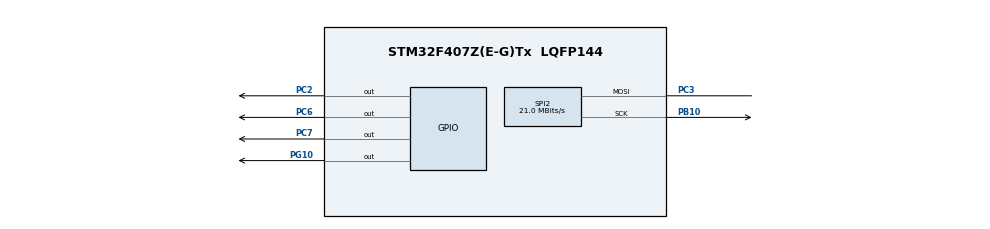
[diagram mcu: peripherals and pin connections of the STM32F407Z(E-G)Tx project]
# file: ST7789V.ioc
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Mcu.Family=STM32F4
Mcu.Name=STM32F407Z(E-G)Tx
Mcu.Package=LQFP144
NVIC.PriorityGroup=NVIC_PRIORITYGROUP_4
PB10.Mode=Simplex_Bidirectional_Master
PB10.Signal=SPI2_SCK
PC2.GPIO_Speed=GPIO_SPEED_FREQ_VERY_HIGH
PC2.Signal=GPIO_Output
PC3.Mode=Simplex_Bidirectional_Master
PC3.Signal=SPI2_MOSI
PC6.GPIO_Speed=GPIO_SPEED_FREQ_VERY_HIGH
PC6.PinState=GPIO_PIN_SET
PC6.Signal=GPIO_Output
PC7.GPIO_Speed=GPIO_SPEED_FREQ_VERY_HIGH
PC7.Signal=GPIO_Output
PG10.GPIO_Speed=GPIO_SPEED_FREQ_VERY_HIGH
PG10.PinState=GPIO_PIN_SET
PG10.Signal=GPIO_Output
PH0-OSC_IN.Mode=HSE-External-Oscillator
PH0-OSC_IN.Signal=RCC_OSC_IN
PH1-OSC_OUT.Mode=HSE-External-Oscillator
PH1-OSC_OUT.Signal=RCC_OSC_OUT
ProjectManager.HeapSize=0x800
ProjectManager.StackSize=0x800
ProjectManager.TargetToolchain=TrueSTUDIO
RCC.48MHZClocksFreq_Value=42000000
RCC.AHBFreq_Value=84000000
RCC.APB1CLKDivider=RCC_HCLK_DIV2
RCC.APB1Freq_Value=42000000
RCC.APB1TimFreq_Value=84000000
RCC.APB2CLKDivider=RCC_HCLK_DIV2
RCC.APB2Freq_Value=42000000
RCC.APB2TimFreq_Value=84000000
RCC.CortexFreq_Value=84000000
RCC.HCLKFreq_Value=84000000
RCC.HSE_VALUE=12000000
RCC.HSI_VALUE=16000000
RCC.LSE_VALUE=32768
RCC.PLLM=6
RCC.PLLN=84
RCC.PLLSourceVirtual=RCC_PLLSOURCE_HSE
RCC.SYSCLKFreq_VALUE=84000000
RCC.SYSCLKSource=RCC_SYSCLKSOURCE_PLLCLK
RCC.VCOOutputFreq_Value=168000000
SPI2.BaudRatePrescaler=SPI_BAUDRATEPRESCALER_2
SPI2.CLKPolarity=SPI_POLARITY_LOW
SPI2.CalculateBaudRate=21.0 MBits/s
SPI2.Direction=SPI_DIRECTION_1LINE
SPI2.Mode=SPI_MODE_MASTER
SPI2.VirtualType=VM_MASTER
board=custom

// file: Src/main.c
/* USER CODE BEGIN Header */
/**
  ******************************************************************************
  * @file           : main.c
  * @brief          : Main program body
  ******************************************************************************
  ** This notice applies to any and all portions of this file
  * that are not between comment pairs USER CODE BEGIN and
  * USER CODE END. Other portions of this file, whether
  * inserted by the user or by software development tools
  * are owned by their respective copyright owners.
  *
  * COPYRIGHT(c) 2019 STMicroelectronics
  *
  * Redistribution and use in source and binary forms, with or without modification,
  * are permitted provided that the following conditions are met:
  *   1. Redistributions of source code must retain the above copyright notice,
  *      this list of conditions and the following disclaimer.
  *   2. Redistributions in binary form must reproduce the above copyright notice,
  *      this list of conditions and the following disclaimer in the documentation
  *      and/or other materials provided with the distribution.
  *   3. Neither the name of STMicroelectronics nor the names of its contributors
  *      may be used to endorse or promote products derived from this software
  *      without specific prior written permission.
  *
  * THIS SOFTWARE IS PROVIDED BY THE COPYRIGHT HOLDERS AND CONTRIBUTORS "AS IS"
  * AND ANY EXPRESS OR IMPLIED WARRANTIES, INCLUDING, BUT NOT LIMITED TO, THE
  * IMPLIED WARRANTIES OF MERCHANTABILITY AND FITNESS FOR A PARTICULAR PURPOSE ARE
  * DISCLAIMED. IN NO EVENT SHALL THE COPYRIGHT HOLDER OR CONTRIBUTORS BE LIABLE
  * FOR ANY DIRECT, INDIRECT, INCIDENTAL, SPECIAL, EXEMPLARY, OR CONSEQUENTIAL
  * DAMAGES (INCLUDING, BUT NOT LIMITED TO, PROCUREMENT OF SUBSTITUTE GOODS OR
  * SERVICES; LOSS OF USE, DATA, OR PROFITS; OR BUSINESS INTERRUPTION) HOWEVER
  * CAUSED AND ON ANY THEORY OF LIABILITY, WHETHER IN CONTRACT, STRICT LIABILITY,
  * OR TORT (INCLUDING NEGLIGENCE OR OTHERWISE) ARISING IN ANY WAY OUT OF THE USE
  * OF THIS SOFTWARE, EVEN IF ADVISED OF THE POSSIBILITY OF SUCH DAMAGE.
  *
  ******************************************************************************
  */
/* USER CODE END Header */

#include "main.h"

/* USER CODE BEGIN Includes */
#include "st7789v.h"
/* USER CODE END Includes */

SPI_HandleTypeDef hspi2;

void SystemClock_Config(void);
static void MX_GPIO_Init(void);
static void MX_SPI2_Init(void);

int main(void)
{

  /* MCU Configuration--------------------------------------------------------*/

  /* Reset of all peripherals, Initializes the Flash interface and the Systick. */
  HAL_Init();

  /* Configure the system clock */
  SystemClock_Config();

  /* Initialize all configured peripherals */
  MX_GPIO_Init();
  MX_SPI2_Init();
  /* USER CODE BEGIN 2 */
  display_init();
  /* USER CODE END 2 */

  /* Infinite loop */
  while (1)
  {

    /* USER CODE BEGIN 3 */
	HAL_GPIO_WritePin(GPIOC, GPIO_PIN_2, 1);
	white_line();
	HAL_GPIO_WritePin(GPIOC, GPIO_PIN_2, 0);
	//white();
	//HAL_Delay(1000);
	black_line();
	//black();
	//HAL_Delay(1000);
  }
  /* USER CODE END 3 */
}

void SystemClock_Config(void)
{
  RCC_OscInitTypeDef RCC_OscInitStruct = {0};
  RCC_ClkInitTypeDef RCC_ClkInitStruct = {0};

  /**Configure the main internal regulator output voltage
  */
  __HAL_RCC_PWR_CLK_ENABLE();
  __HAL_PWR_VOLTAGESCALING_CONFIG(PWR_REGULATOR_VOLTAGE_SCALE1);
  /**Initializes the CPU, AHB and APB busses clocks
  */
  RCC_OscInitStruct.OscillatorType = RCC_OSCILLATORTYPE_HSE;
  RCC_OscInitStruct.HSEState = RCC_HSE_ON;
  RCC_OscInitStruct.PLL.PLLState = RCC_PLL_ON;
  RCC_OscInitStruct.PLL.PLLSource = RCC_PLLSOURCE_HSE;
  RCC_OscInitStruct.PLL.PLLM = 6;
  RCC_OscInitStruct.PLL.PLLN = 84;
  RCC_OscInitStruct.PLL.PLLP = RCC_PLLP_DIV2;
  RCC_OscInitStruct.PLL.PLLQ = 4;
  if (HAL_RCC_OscConfig(&RCC_OscInitStruct) != HAL_OK)
  {
    Error_Handler();
  }
  /**Initializes the CPU, AHB and APB busses clocks
  */
  RCC_ClkInitStruct.ClockType = RCC_CLOCKTYPE_HCLK|RCC_CLOCKTYPE_SYSCLK
                              |RCC_CLOCKTYPE_PCLK1|RCC_CLOCKTYPE_PCLK2;
  RCC_ClkInitStruct.SYSCLKSource = RCC_SYSCLKSOURCE_PLLCLK;
  RCC_ClkInitStruct.AHBCLKDivider = RCC_SYSCLK_DIV1;
  RCC_ClkInitStruct.APB1CLKDivider = RCC_HCLK_DIV1;
  RCC_ClkInitStruct.APB2CLKDivider = RCC_HCLK_DIV2;

  if (HAL_RCC_ClockConfig(&RCC_ClkInitStruct, FLASH_LATENCY_2) != HAL_OK)
  {
    Error_Handler();
  }
}

static void MX_SPI2_Init(void)
{

  /* SPI2 parameter configuration*/
  hspi2.Instance = SPI2;
  hspi2.Init.Mode = SPI_MODE_MASTER;
  hspi2.Init.Direction = SPI_DIRECTION_1LINE;
  hspi2.Init.DataSize = SPI_DATASIZE_8BIT;
  hspi2.Init.CLKPolarity = SPI_POLARITY_LOW;
  hspi2.Init.CLKPhase = SPI_PHASE_1EDGE;
  hspi2.Init.NSS = SPI_NSS_SOFT;
  hspi2.Init.BaudRatePrescaler = SPI_BAUDRATEPRESCALER_2;
  hspi2.Init.FirstBit = SPI_FIRSTBIT_MSB;
  hspi2.Init.TIMode = SPI_TIMODE_DISABLE;
  hspi2.Init.CRCCalculation = SPI_CRCCALCULATION_DISABLE;
  hspi2.Init.CRCPolynomial = 10;
  if (HAL_SPI_Init(&hspi2) != HAL_OK)
  {
    Error_Handler();
  }

}

static void MX_GPIO_Init(void)
{
  GPIO_InitTypeDef GPIO_InitStruct = {0};

  /* GPIO Ports Clock Enable */
  __HAL_RCC_GPIOH_CLK_ENABLE();
  __HAL_RCC_GPIOC_CLK_ENABLE();
  __HAL_RCC_GPIOB_CLK_ENABLE();
  __HAL_RCC_GPIOG_CLK_ENABLE();

  /*Configure GPIO pin Output Level */
  HAL_GPIO_WritePin(GPIOC, GPIO_PIN_2|GPIO_PIN_7, GPIO_PIN_RESET);

  /*Configure GPIO pin Output Level */
  HAL_GPIO_WritePin(GPIOC, GPIO_PIN_6, GPIO_PIN_SET);

  /*Configure GPIO pin Output Level */
  HAL_GPIO_WritePin(GPIOG, GPIO_PIN_10, GPIO_PIN_SET);

  /*Configure GPIO pins : PC2 PC6 PC7 */
  GPIO_InitStruct.Pin = GPIO_PIN_2|GPIO_PIN_6|GPIO_PIN_7;
  GPIO_InitStruct.Mode = GPIO_MODE_OUTPUT_PP;
  GPIO_InitStruct.Pull = GPIO_NOPULL;
  GPIO_InitStruct.Speed = GPIO_SPEED_FREQ_VERY_HIGH;
  HAL_GPIO_Init(GPIOC, &GPIO_InitStruct);

  /*Configure GPIO pin : PG10 */
  GPIO_InitStruct.Pin = GPIO_PIN_10;
  GPIO_InitStruct.Mode = GPIO_MODE_OUTPUT_PP;
  GPIO_InitStruct.Pull = GPIO_NOPULL;
  GPIO_InitStruct.Speed = GPIO_SPEED_FREQ_VERY_HIGH;
  HAL_GPIO_Init(GPIOG, &GPIO_InitStruct);

}

void Error_Handler(void)
{
}

/************************ (C) COPYRIGHT STMicroelectronics *****END OF FILE****/
